VERSION 5.7 ;
BUSBITCHARS "[]" ;
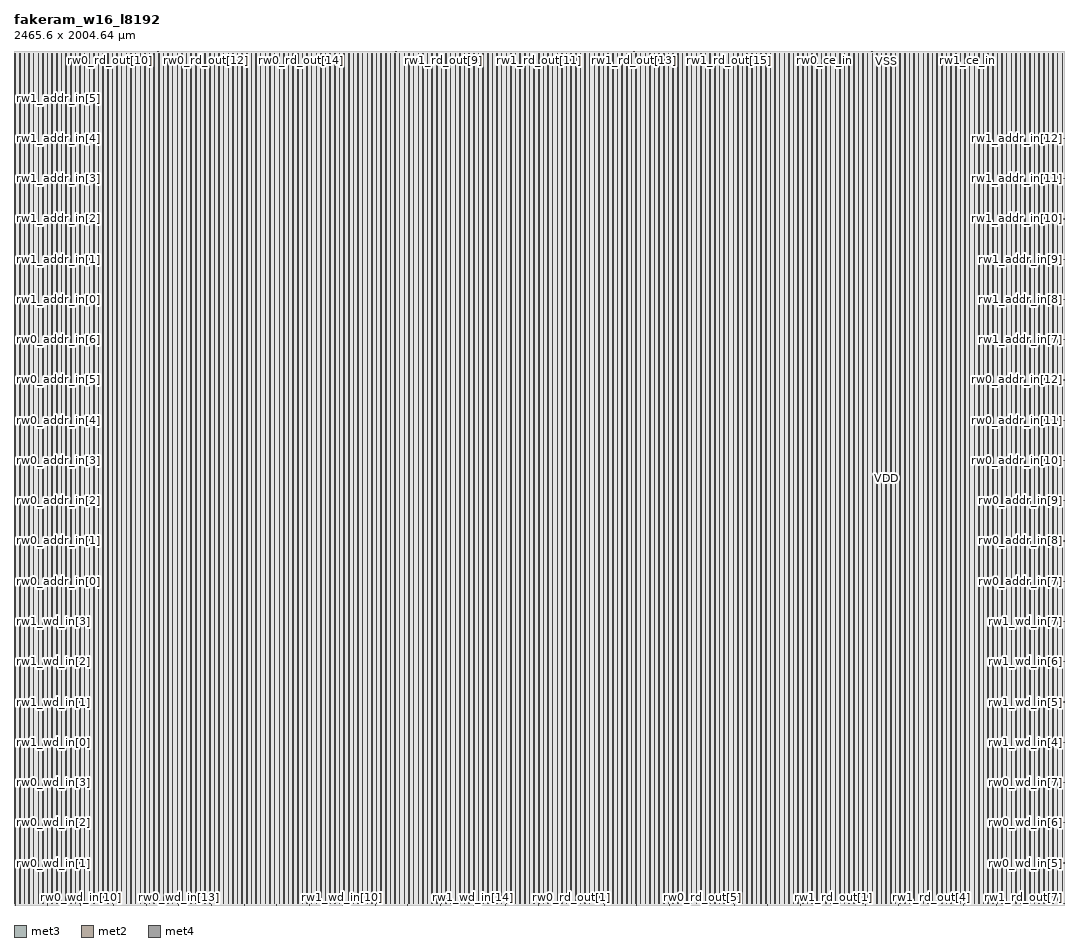
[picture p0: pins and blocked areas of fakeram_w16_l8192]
MACRO fakeram_w16_l8192
  FOREIGN fakeram_w16_l8192 0 0 ;
  SYMMETRY X Y R90 ;
  SIZE 2465.600 BY 2004.640 ;
  CLASS BLOCK ;
  PIN rw0_wd_in[0]
    DIRECTION INPUT ;
    USE SIGNAL ;
    SHAPE ABUTMENT ;
    PORT
      LAYER met3 ;
      RECT 0.000 3.930 0.900 4.230 ;
    END
  END rw0_wd_in[0]
  PIN rw0_wd_in[1]
    DIRECTION INPUT ;
    USE SIGNAL ;
    SHAPE ABUTMENT ;
    PORT
      LAYER met3 ;
      RECT 0.000 98.450 0.900 98.750 ;
    END
  END rw0_wd_in[1]
  PIN rw0_wd_in[2]
    DIRECTION INPUT ;
    USE SIGNAL ;
    SHAPE ABUTMENT ;
    PORT
      LAYER met3 ;
      RECT 0.000 192.970 0.900 193.270 ;
    END
  END rw0_wd_in[2]
  PIN rw0_wd_in[3]
    DIRECTION INPUT ;
    USE SIGNAL ;
    SHAPE ABUTMENT ;
    PORT
      LAYER met3 ;
      RECT 0.000 287.490 0.900 287.790 ;
    END
  END rw0_wd_in[3]
  PIN rw0_wd_in[4]
    DIRECTION INPUT ;
    USE SIGNAL ;
    SHAPE ABUTMENT ;
    PORT
      LAYER met3 ;
      RECT 2464.700 3.930 2465.600 4.230 ;
    END
  END rw0_wd_in[4]
  PIN rw0_wd_in[5]
    DIRECTION INPUT ;
    USE SIGNAL ;
    SHAPE ABUTMENT ;
    PORT
      LAYER met3 ;
      RECT 2464.700 98.450 2465.600 98.750 ;
    END
  END rw0_wd_in[5]
  PIN rw0_wd_in[6]
    DIRECTION INPUT ;
    USE SIGNAL ;
    SHAPE ABUTMENT ;
    PORT
      LAYER met3 ;
      RECT 2464.700 192.970 2465.600 193.270 ;
    END
  END rw0_wd_in[6]
  PIN rw0_wd_in[7]
    DIRECTION INPUT ;
    USE SIGNAL ;
    SHAPE ABUTMENT ;
    PORT
      LAYER met3 ;
      RECT 2464.700 287.490 2465.600 287.790 ;
    END
  END rw0_wd_in[7]
  PIN rw0_wd_in[8]
    DIRECTION INPUT ;
    USE SIGNAL ;
    SHAPE ABUTMENT ;
    PORT
      LAYER met2 ;
      RECT 2.690 0.000 2.830 0.420 ;
    END
  END rw0_wd_in[8]
  PIN rw0_wd_in[9]
    DIRECTION INPUT ;
    USE SIGNAL ;
    SHAPE ABUTMENT ;
    PORT
      LAYER met2 ;
      RECT 79.510 0.000 79.650 0.420 ;
    END
  END rw0_wd_in[9]
  PIN rw0_wd_in[10]
    DIRECTION INPUT ;
    USE SIGNAL ;
    SHAPE ABUTMENT ;
    PORT
      LAYER met2 ;
      RECT 156.330 0.000 156.470 0.420 ;
    END
  END rw0_wd_in[10]
  PIN rw0_wd_in[11]
    DIRECTION INPUT ;
    USE SIGNAL ;
    SHAPE ABUTMENT ;
    PORT
      LAYER met2 ;
      RECT 233.150 0.000 233.290 0.420 ;
    END
  END rw0_wd_in[11]
  PIN rw0_wd_in[12]
    DIRECTION INPUT ;
    USE SIGNAL ;
    SHAPE ABUTMENT ;
    PORT
      LAYER met2 ;
      RECT 309.970 0.000 310.110 0.420 ;
    END
  END rw0_wd_in[12]
  PIN rw0_wd_in[13]
    DIRECTION INPUT ;
    USE SIGNAL ;
    SHAPE ABUTMENT ;
    PORT
      LAYER met2 ;
      RECT 386.790 0.000 386.930 0.420 ;
    END
  END rw0_wd_in[13]
  PIN rw0_wd_in[14]
    DIRECTION INPUT ;
    USE SIGNAL ;
    SHAPE ABUTMENT ;
    PORT
      LAYER met2 ;
      RECT 463.610 0.000 463.750 0.420 ;
    END
  END rw0_wd_in[14]
  PIN rw0_wd_in[15]
    DIRECTION INPUT ;
    USE SIGNAL ;
    SHAPE ABUTMENT ;
    PORT
      LAYER met2 ;
      RECT 540.430 0.000 540.570 0.420 ;
    END
  END rw0_wd_in[15]
  PIN rw1_wd_in[0]
    DIRECTION INPUT ;
    USE SIGNAL ;
    SHAPE ABUTMENT ;
    PORT
      LAYER met3 ;
      RECT 0.000 382.010 0.900 382.310 ;
    END
  END rw1_wd_in[0]
  PIN rw1_wd_in[1]
    DIRECTION INPUT ;
    USE SIGNAL ;
    SHAPE ABUTMENT ;
    PORT
      LAYER met3 ;
      RECT 0.000 476.530 0.900 476.830 ;
    END
  END rw1_wd_in[1]
  PIN rw1_wd_in[2]
    DIRECTION INPUT ;
    USE SIGNAL ;
    SHAPE ABUTMENT ;
    PORT
      LAYER met3 ;
      RECT 0.000 571.050 0.900 571.350 ;
    END
  END rw1_wd_in[2]
  PIN rw1_wd_in[3]
    DIRECTION INPUT ;
    USE SIGNAL ;
    SHAPE ABUTMENT ;
    PORT
      LAYER met3 ;
      RECT 0.000 665.570 0.900 665.870 ;
    END
  END rw1_wd_in[3]
  PIN rw1_wd_in[4]
    DIRECTION INPUT ;
    USE SIGNAL ;
    SHAPE ABUTMENT ;
    PORT
      LAYER met3 ;
      RECT 2464.700 382.010 2465.600 382.310 ;
    END
  END rw1_wd_in[4]
  PIN rw1_wd_in[5]
    DIRECTION INPUT ;
    USE SIGNAL ;
    SHAPE ABUTMENT ;
    PORT
      LAYER met3 ;
      RECT 2464.700 476.530 2465.600 476.830 ;
    END
  END rw1_wd_in[5]
  PIN rw1_wd_in[6]
    DIRECTION INPUT ;
    USE SIGNAL ;
    SHAPE ABUTMENT ;
    PORT
      LAYER met3 ;
      RECT 2464.700 571.050 2465.600 571.350 ;
    END
  END rw1_wd_in[6]
  PIN rw1_wd_in[7]
    DIRECTION INPUT ;
    USE SIGNAL ;
    SHAPE ABUTMENT ;
    PORT
      LAYER met3 ;
      RECT 2464.700 665.570 2465.600 665.870 ;
    END
  END rw1_wd_in[7]
  PIN rw1_wd_in[8]
    DIRECTION INPUT ;
    USE SIGNAL ;
    SHAPE ABUTMENT ;
    PORT
      LAYER met2 ;
      RECT 617.250 0.000 617.390 0.420 ;
    END
  END rw1_wd_in[8]
  PIN rw1_wd_in[9]
    DIRECTION INPUT ;
    USE SIGNAL ;
    SHAPE ABUTMENT ;
    PORT
      LAYER met2 ;
      RECT 694.070 0.000 694.210 0.420 ;
    END
  END rw1_wd_in[9]
  PIN rw1_wd_in[10]
    DIRECTION INPUT ;
    USE SIGNAL ;
    SHAPE ABUTMENT ;
    PORT
      LAYER met2 ;
      RECT 770.890 0.000 771.030 0.420 ;
    END
  END rw1_wd_in[10]
  PIN rw1_wd_in[11]
    DIRECTION INPUT ;
    USE SIGNAL ;
    SHAPE ABUTMENT ;
    PORT
      LAYER met2 ;
      RECT 847.710 0.000 847.850 0.420 ;
    END
  END rw1_wd_in[11]
  PIN rw1_wd_in[12]
    DIRECTION INPUT ;
    USE SIGNAL ;
    SHAPE ABUTMENT ;
    PORT
      LAYER met2 ;
      RECT 924.530 0.000 924.670 0.420 ;
    END
  END rw1_wd_in[12]
  PIN rw1_wd_in[13]
    DIRECTION INPUT ;
    USE SIGNAL ;
    SHAPE ABUTMENT ;
    PORT
      LAYER met2 ;
      RECT 1001.350 0.000 1001.490 0.420 ;
    END
  END rw1_wd_in[13]
  PIN rw1_wd_in[14]
    DIRECTION INPUT ;
    USE SIGNAL ;
    SHAPE ABUTMENT ;
    PORT
      LAYER met2 ;
      RECT 1078.170 0.000 1078.310 0.420 ;
    END
  END rw1_wd_in[14]
  PIN rw1_wd_in[15]
    DIRECTION INPUT ;
    USE SIGNAL ;
    SHAPE ABUTMENT ;
    PORT
      LAYER met2 ;
      RECT 1154.990 0.000 1155.130 0.420 ;
    END
  END rw1_wd_in[15]
  PIN rw0_rd_out[0]
    DIRECTION OUTPUT ;
    USE SIGNAL ;
    SHAPE ABUTMENT ;
    PORT
      LAYER met2 ;
      RECT 1231.810 0.000 1231.950 0.420 ;
    END
  END rw0_rd_out[0]
  PIN rw0_rd_out[1]
    DIRECTION OUTPUT ;
    USE SIGNAL ;
    SHAPE ABUTMENT ;
    PORT
      LAYER met2 ;
      RECT 1308.630 0.000 1308.770 0.420 ;
    END
  END rw0_rd_out[1]
  PIN rw0_rd_out[2]
    DIRECTION OUTPUT ;
    USE SIGNAL ;
    SHAPE ABUTMENT ;
    PORT
      LAYER met2 ;
      RECT 1385.450 0.000 1385.590 0.420 ;
    END
  END rw0_rd_out[2]
  PIN rw0_rd_out[3]
    DIRECTION OUTPUT ;
    USE SIGNAL ;
    SHAPE ABUTMENT ;
    PORT
      LAYER met2 ;
      RECT 1462.270 0.000 1462.410 0.420 ;
    END
  END rw0_rd_out[3]
  PIN rw0_rd_out[4]
    DIRECTION OUTPUT ;
    USE SIGNAL ;
    SHAPE ABUTMENT ;
    PORT
      LAYER met2 ;
      RECT 1539.090 0.000 1539.230 0.420 ;
    END
  END rw0_rd_out[4]
  PIN rw0_rd_out[5]
    DIRECTION OUTPUT ;
    USE SIGNAL ;
    SHAPE ABUTMENT ;
    PORT
      LAYER met2 ;
      RECT 1615.910 0.000 1616.050 0.420 ;
    END
  END rw0_rd_out[5]
  PIN rw0_rd_out[6]
    DIRECTION OUTPUT ;
    USE SIGNAL ;
    SHAPE ABUTMENT ;
    PORT
      LAYER met2 ;
      RECT 1692.730 0.000 1692.870 0.420 ;
    END
  END rw0_rd_out[6]
  PIN rw0_rd_out[7]
    DIRECTION OUTPUT ;
    USE SIGNAL ;
    SHAPE ABUTMENT ;
    PORT
      LAYER met2 ;
      RECT 1769.550 0.000 1769.690 0.420 ;
    END
  END rw0_rd_out[7]
  PIN rw0_rd_out[8]
    DIRECTION OUTPUT ;
    USE SIGNAL ;
    SHAPE ABUTMENT ;
    PORT
      LAYER met2 ;
      RECT 2.690 2004.220 2.830 2004.640 ;
    END
  END rw0_rd_out[8]
  PIN rw0_rd_out[9]
    DIRECTION OUTPUT ;
    USE SIGNAL ;
    SHAPE ABUTMENT ;
    PORT
      LAYER met2 ;
      RECT 114.470 2004.220 114.610 2004.640 ;
    END
  END rw0_rd_out[9]
  PIN rw0_rd_out[10]
    DIRECTION OUTPUT ;
    USE SIGNAL ;
    SHAPE ABUTMENT ;
    PORT
      LAYER met2 ;
      RECT 226.250 2004.220 226.390 2004.640 ;
    END
  END rw0_rd_out[10]
  PIN rw0_rd_out[11]
    DIRECTION OUTPUT ;
    USE SIGNAL ;
    SHAPE ABUTMENT ;
    PORT
      LAYER met2 ;
      RECT 338.030 2004.220 338.170 2004.640 ;
    END
  END rw0_rd_out[11]
  PIN rw0_rd_out[12]
    DIRECTION OUTPUT ;
    USE SIGNAL ;
    SHAPE ABUTMENT ;
    PORT
      LAYER met2 ;
      RECT 449.810 2004.220 449.950 2004.640 ;
    END
  END rw0_rd_out[12]
  PIN rw0_rd_out[13]
    DIRECTION OUTPUT ;
    USE SIGNAL ;
    SHAPE ABUTMENT ;
    PORT
      LAYER met2 ;
      RECT 561.590 2004.220 561.730 2004.640 ;
    END
  END rw0_rd_out[13]
  PIN rw0_rd_out[14]
    DIRECTION OUTPUT ;
    USE SIGNAL ;
    SHAPE ABUTMENT ;
    PORT
      LAYER met2 ;
      RECT 673.370 2004.220 673.510 2004.640 ;
    END
  END rw0_rd_out[14]
  PIN rw0_rd_out[15]
    DIRECTION OUTPUT ;
    USE SIGNAL ;
    SHAPE ABUTMENT ;
    PORT
      LAYER met2 ;
      RECT 785.150 2004.220 785.290 2004.640 ;
    END
  END rw0_rd_out[15]
  PIN rw1_rd_out[0]
    DIRECTION OUTPUT ;
    USE SIGNAL ;
    SHAPE ABUTMENT ;
    PORT
      LAYER met2 ;
      RECT 1846.370 0.000 1846.510 0.420 ;
    END
  END rw1_rd_out[0]
  PIN rw1_rd_out[1]
    DIRECTION OUTPUT ;
    USE SIGNAL ;
    SHAPE ABUTMENT ;
    PORT
      LAYER met2 ;
      RECT 1923.190 0.000 1923.330 0.420 ;
    END
  END rw1_rd_out[1]
  PIN rw1_rd_out[2]
    DIRECTION OUTPUT ;
    USE SIGNAL ;
    SHAPE ABUTMENT ;
    PORT
      LAYER met2 ;
      RECT 2000.010 0.000 2000.150 0.420 ;
    END
  END rw1_rd_out[2]
  PIN rw1_rd_out[3]
    DIRECTION OUTPUT ;
    USE SIGNAL ;
    SHAPE ABUTMENT ;
    PORT
      LAYER met2 ;
      RECT 2076.830 0.000 2076.970 0.420 ;
    END
  END rw1_rd_out[3]
  PIN rw1_rd_out[4]
    DIRECTION OUTPUT ;
    USE SIGNAL ;
    SHAPE ABUTMENT ;
    PORT
      LAYER met2 ;
      RECT 2153.650 0.000 2153.790 0.420 ;
    END
  END rw1_rd_out[4]
  PIN rw1_rd_out[5]
    DIRECTION OUTPUT ;
    USE SIGNAL ;
    SHAPE ABUTMENT ;
    PORT
      LAYER met2 ;
      RECT 2230.470 0.000 2230.610 0.420 ;
    END
  END rw1_rd_out[5]
  PIN rw1_rd_out[6]
    DIRECTION OUTPUT ;
    USE SIGNAL ;
    SHAPE ABUTMENT ;
    PORT
      LAYER met2 ;
      RECT 2307.290 0.000 2307.430 0.420 ;
    END
  END rw1_rd_out[6]
  PIN rw1_rd_out[7]
    DIRECTION OUTPUT ;
    USE SIGNAL ;
    SHAPE ABUTMENT ;
    PORT
      LAYER met2 ;
      RECT 2384.110 0.000 2384.250 0.420 ;
    END
  END rw1_rd_out[7]
  PIN rw1_rd_out[8]
    DIRECTION OUTPUT ;
    USE SIGNAL ;
    SHAPE ABUTMENT ;
    PORT
      LAYER met2 ;
      RECT 896.930 2004.220 897.070 2004.640 ;
    END
  END rw1_rd_out[8]
  PIN rw1_rd_out[9]
    DIRECTION OUTPUT ;
    USE SIGNAL ;
    SHAPE ABUTMENT ;
    PORT
      LAYER met2 ;
      RECT 1008.710 2004.220 1008.850 2004.640 ;
    END
  END rw1_rd_out[9]
  PIN rw1_rd_out[10]
    DIRECTION OUTPUT ;
    USE SIGNAL ;
    SHAPE ABUTMENT ;
    PORT
      LAYER met2 ;
      RECT 1120.490 2004.220 1120.630 2004.640 ;
    END
  END rw1_rd_out[10]
  PIN rw1_rd_out[11]
    DIRECTION OUTPUT ;
    USE SIGNAL ;
    SHAPE ABUTMENT ;
    PORT
      LAYER met2 ;
      RECT 1232.270 2004.220 1232.410 2004.640 ;
    END
  END rw1_rd_out[11]
  PIN rw1_rd_out[12]
    DIRECTION OUTPUT ;
    USE SIGNAL ;
    SHAPE ABUTMENT ;
    PORT
      LAYER met2 ;
      RECT 1344.050 2004.220 1344.190 2004.640 ;
    END
  END rw1_rd_out[12]
  PIN rw1_rd_out[13]
    DIRECTION OUTPUT ;
    USE SIGNAL ;
    SHAPE ABUTMENT ;
    PORT
      LAYER met2 ;
      RECT 1455.830 2004.220 1455.970 2004.640 ;
    END
  END rw1_rd_out[13]
  PIN rw1_rd_out[14]
    DIRECTION OUTPUT ;
    USE SIGNAL ;
    SHAPE ABUTMENT ;
    PORT
      LAYER met2 ;
      RECT 1567.610 2004.220 1567.750 2004.640 ;
    END
  END rw1_rd_out[14]
  PIN rw1_rd_out[15]
    DIRECTION OUTPUT ;
    USE SIGNAL ;
    SHAPE ABUTMENT ;
    PORT
      LAYER met2 ;
      RECT 1679.390 2004.220 1679.530 2004.640 ;
    END
  END rw1_rd_out[15]
  PIN rw0_addr_in[0]
    DIRECTION INPUT ;
    USE SIGNAL ;
    SHAPE ABUTMENT ;
    PORT
      LAYER met3 ;
      RECT 0.000 760.090 0.900 760.390 ;
    END
  END rw0_addr_in[0]
  PIN rw0_addr_in[1]
    DIRECTION INPUT ;
    USE SIGNAL ;
    SHAPE ABUTMENT ;
    PORT
      LAYER met3 ;
      RECT 0.000 854.610 0.900 854.910 ;
    END
  END rw0_addr_in[1]
  PIN rw0_addr_in[2]
    DIRECTION INPUT ;
    USE SIGNAL ;
    SHAPE ABUTMENT ;
    PORT
      LAYER met3 ;
      RECT 0.000 949.130 0.900 949.430 ;
    END
  END rw0_addr_in[2]
  PIN rw0_addr_in[3]
    DIRECTION INPUT ;
    USE SIGNAL ;
    SHAPE ABUTMENT ;
    PORT
      LAYER met3 ;
      RECT 0.000 1043.650 0.900 1043.950 ;
    END
  END rw0_addr_in[3]
  PIN rw0_addr_in[4]
    DIRECTION INPUT ;
    USE SIGNAL ;
    SHAPE ABUTMENT ;
    PORT
      LAYER met3 ;
      RECT 0.000 1138.170 0.900 1138.470 ;
    END
  END rw0_addr_in[4]
  PIN rw0_addr_in[5]
    DIRECTION INPUT ;
    USE SIGNAL ;
    SHAPE ABUTMENT ;
    PORT
      LAYER met3 ;
      RECT 0.000 1232.690 0.900 1232.990 ;
    END
  END rw0_addr_in[5]
  PIN rw0_addr_in[6]
    DIRECTION INPUT ;
    USE SIGNAL ;
    SHAPE ABUTMENT ;
    PORT
      LAYER met3 ;
      RECT 0.000 1327.210 0.900 1327.510 ;
    END
  END rw0_addr_in[6]
  PIN rw0_addr_in[7]
    DIRECTION INPUT ;
    USE SIGNAL ;
    SHAPE ABUTMENT ;
    PORT
      LAYER met3 ;
      RECT 2464.700 760.090 2465.600 760.390 ;
    END
  END rw0_addr_in[7]
  PIN rw0_addr_in[8]
    DIRECTION INPUT ;
    USE SIGNAL ;
    SHAPE ABUTMENT ;
    PORT
      LAYER met3 ;
      RECT 2464.700 854.610 2465.600 854.910 ;
    END
  END rw0_addr_in[8]
  PIN rw0_addr_in[9]
    DIRECTION INPUT ;
    USE SIGNAL ;
    SHAPE ABUTMENT ;
    PORT
      LAYER met3 ;
      RECT 2464.700 949.130 2465.600 949.430 ;
    END
  END rw0_addr_in[9]
  PIN rw0_addr_in[10]
    DIRECTION INPUT ;
    USE SIGNAL ;
    SHAPE ABUTMENT ;
    PORT
      LAYER met3 ;
      RECT 2464.700 1043.650 2465.600 1043.950 ;
    END
  END rw0_addr_in[10]
  PIN rw0_addr_in[11]
    DIRECTION INPUT ;
    USE SIGNAL ;
    SHAPE ABUTMENT ;
    PORT
      LAYER met3 ;
      RECT 2464.700 1138.170 2465.600 1138.470 ;
    END
  END rw0_addr_in[11]
  PIN rw0_addr_in[12]
    DIRECTION INPUT ;
    USE SIGNAL ;
    SHAPE ABUTMENT ;
    PORT
      LAYER met3 ;
      RECT 2464.700 1232.690 2465.600 1232.990 ;
    END
  END rw0_addr_in[12]
  PIN rw1_addr_in[0]
    DIRECTION INPUT ;
    USE SIGNAL ;
    SHAPE ABUTMENT ;
    PORT
      LAYER met3 ;
      RECT 0.000 1421.730 0.900 1422.030 ;
    END
  END rw1_addr_in[0]
  PIN rw1_addr_in[1]
    DIRECTION INPUT ;
    USE SIGNAL ;
    SHAPE ABUTMENT ;
    PORT
      LAYER met3 ;
      RECT 0.000 1516.250 0.900 1516.550 ;
    END
  END rw1_addr_in[1]
  PIN rw1_addr_in[2]
    DIRECTION INPUT ;
    USE SIGNAL ;
    SHAPE ABUTMENT ;
    PORT
      LAYER met3 ;
      RECT 0.000 1610.770 0.900 1611.070 ;
    END
  END rw1_addr_in[2]
  PIN rw1_addr_in[3]
    DIRECTION INPUT ;
    USE SIGNAL ;
    SHAPE ABUTMENT ;
    PORT
      LAYER met3 ;
      RECT 0.000 1705.290 0.900 1705.590 ;
    END
  END rw1_addr_in[3]
  PIN rw1_addr_in[4]
    DIRECTION INPUT ;
    USE SIGNAL ;
    SHAPE ABUTMENT ;
    PORT
      LAYER met3 ;
      RECT 0.000 1799.810 0.900 1800.110 ;
    END
  END rw1_addr_in[4]
  PIN rw1_addr_in[5]
    DIRECTION INPUT ;
    USE SIGNAL ;
    SHAPE ABUTMENT ;
    PORT
      LAYER met3 ;
      RECT 0.000 1894.330 0.900 1894.630 ;
    END
  END rw1_addr_in[5]
  PIN rw1_addr_in[6]
    DIRECTION INPUT ;
    USE SIGNAL ;
    SHAPE ABUTMENT ;
    PORT
      LAYER met3 ;
      RECT 0.000 1988.850 0.900 1989.150 ;
    END
  END rw1_addr_in[6]
  PIN rw1_addr_in[7]
    DIRECTION INPUT ;
    USE SIGNAL ;
    SHAPE ABUTMENT ;
    PORT
      LAYER met3 ;
      RECT 2464.700 1327.210 2465.600 1327.510 ;
    END
  END rw1_addr_in[7]
  PIN rw1_addr_in[8]
    DIRECTION INPUT ;
    USE SIGNAL ;
    SHAPE ABUTMENT ;
    PORT
      LAYER met3 ;
      RECT 2464.700 1421.730 2465.600 1422.030 ;
    END
  END rw1_addr_in[8]
  PIN rw1_addr_in[9]
    DIRECTION INPUT ;
    USE SIGNAL ;
    SHAPE ABUTMENT ;
    PORT
      LAYER met3 ;
      RECT 2464.700 1516.250 2465.600 1516.550 ;
    END
  END rw1_addr_in[9]
  PIN rw1_addr_in[10]
    DIRECTION INPUT ;
    USE SIGNAL ;
    SHAPE ABUTMENT ;
    PORT
      LAYER met3 ;
      RECT 2464.700 1610.770 2465.600 1611.070 ;
    END
  END rw1_addr_in[10]
  PIN rw1_addr_in[11]
    DIRECTION INPUT ;
    USE SIGNAL ;
    SHAPE ABUTMENT ;
    PORT
      LAYER met3 ;
      RECT 2464.700 1705.290 2465.600 1705.590 ;
    END
  END rw1_addr_in[11]
  PIN rw1_addr_in[12]
    DIRECTION INPUT ;
    USE SIGNAL ;
    SHAPE ABUTMENT ;
    PORT
      LAYER met3 ;
      RECT 2464.700 1799.810 2465.600 1800.110 ;
    END
  END rw1_addr_in[12]
  PIN rw0_we_in
    DIRECTION INPUT ;
    USE SIGNAL ;
    SHAPE ABUTMENT ;
    PORT
      LAYER met2 ;
      RECT 1791.170 2004.220 1791.310 2004.640 ;
    END
  END rw0_we_in
  PIN rw0_ce_in
    DIRECTION INPUT ;
    USE SIGNAL ;
    SHAPE ABUTMENT ;
    PORT
      LAYER met2 ;
      RECT 1902.950 2004.220 1903.090 2004.640 ;
    END
  END rw0_ce_in
  PIN rw0_clk
    DIRECTION INPUT ;
    USE SIGNAL ;
    SHAPE ABUTMENT ;
    PORT
      LAYER met2 ;
      RECT 2014.730 2004.220 2014.870 2004.640 ;
    END
  END rw0_clk
  PIN rw1_we_in
    DIRECTION INPUT ;
    USE SIGNAL ;
    SHAPE ABUTMENT ;
    PORT
      LAYER met2 ;
      RECT 2126.510 2004.220 2126.650 2004.640 ;
    END
  END rw1_we_in
  PIN rw1_ce_in
    DIRECTION INPUT ;
    USE SIGNAL ;
    SHAPE ABUTMENT ;
    PORT
      LAYER met2 ;
      RECT 2238.290 2004.220 2238.430 2004.640 ;
    END
  END rw1_ce_in
  PIN rw1_clk
    DIRECTION INPUT ;
    USE SIGNAL ;
    SHAPE ABUTMENT ;
    PORT
      LAYER met2 ;
      RECT 2350.070 2004.220 2350.210 2004.640 ;
    END
  END rw1_clk
  PIN VSS
    DIRECTION INOUT ;
    USE GROUND ;
    PORT
      LAYER met4 ;
      RECT 2.160 4.080 3.360 2000.560 ;
      RECT 13.040 4.080 14.240 2000.560 ;
      RECT 23.920 4.080 25.120 2000.560 ;
      RECT 34.800 4.080 36.000 2000.560 ;
      RECT 45.680 4.080 46.880 2000.560 ;
      RECT 56.560 4.080 57.760 2000.560 ;
      RECT 67.440 4.080 68.640 2000.560 ;
      RECT 78.320 4.080 79.520 2000.560 ;
      RECT 89.200 4.080 90.400 2000.560 ;
      RECT 100.080 4.080 101.280 2000.560 ;
      RECT 110.960 4.080 112.160 2000.560 ;
      RECT 121.840 4.080 123.040 2000.560 ;
      RECT 132.720 4.080 133.920 2000.560 ;
      RECT 143.600 4.080 144.800 2000.560 ;
      RECT 154.480 4.080 155.680 2000.560 ;
      RECT 165.360 4.080 166.560 2000.560 ;
      RECT 176.240 4.080 177.440 2000.560 ;
      RECT 187.120 4.080 188.320 2000.560 ;
      RECT 198.000 4.080 199.200 2000.560 ;
      RECT 208.880 4.080 210.080 2000.560 ;
      RECT 219.760 4.080 220.960 2000.560 ;
      RECT 230.640 4.080 231.840 2000.560 ;
      RECT 241.520 4.080 242.720 2000.560 ;
      RECT 252.400 4.080 253.600 2000.560 ;
      RECT 263.280 4.080 264.480 2000.560 ;
      RECT 274.160 4.080 275.360 2000.560 ;
      RECT 285.040 4.080 286.240 2000.560 ;
      RECT 295.920 4.080 297.120 2000.560 ;
      RECT 306.800 4.080 308.000 2000.560 ;
      RECT 317.680 4.080 318.880 2000.560 ;
      RECT 328.560 4.080 329.760 2000.560 ;
      RECT 339.440 4.080 340.640 2000.560 ;
      RECT 350.320 4.080 351.520 2000.560 ;
      RECT 361.200 4.080 362.400 2000.560 ;
      RECT 372.080 4.080 373.280 2000.560 ;
      RECT 382.960 4.080 384.160 2000.560 ;
      RECT 393.840 4.080 395.040 2000.560 ;
      RECT 404.720 4.080 405.920 2000.560 ;
      RECT 415.600 4.080 416.800 2000.560 ;
      RECT 426.480 4.080 427.680 2000.560 ;
      RECT 437.360 4.080 438.560 2000.560 ;
      RECT 448.240 4.080 449.440 2000.560 ;
      RECT 459.120 4.080 460.320 2000.560 ;
      RECT 470.000 4.080 471.200 2000.560 ;
      RECT 480.880 4.080 482.080 2000.560 ;
      RECT 491.760 4.080 492.960 2000.560 ;
      RECT 502.640 4.080 503.840 2000.560 ;
      RECT 513.520 4.080 514.720 2000.560 ;
      RECT 524.400 4.080 525.600 2000.560 ;
      RECT 535.280 4.080 536.480 2000.560 ;
      RECT 546.160 4.080 547.360 2000.560 ;
      RECT 557.040 4.080 558.240 2000.560 ;
      RECT 567.920 4.080 569.120 2000.560 ;
      RECT 578.800 4.080 580.000 2000.560 ;
      RECT 589.680 4.080 590.880 2000.560 ;
      RECT 600.560 4.080 601.760 2000.560 ;
      RECT 611.440 4.080 612.640 2000.560 ;
      RECT 622.320 4.080 623.520 2000.560 ;
      RECT 633.200 4.080 634.400 2000.560 ;
      RECT 644.080 4.080 645.280 2000.560 ;
      RECT 654.960 4.080 656.160 2000.560 ;
      RECT 665.840 4.080 667.040 2000.560 ;
      RECT 676.720 4.080 677.920 2000.560 ;
      RECT 687.600 4.080 688.800 2000.560 ;
      RECT 698.480 4.080 699.680 2000.560 ;
      RECT 709.360 4.080 710.560 2000.560 ;
      RECT 720.240 4.080 721.440 2000.560 ;
      RECT 731.120 4.080 732.320 2000.560 ;
      RECT 742.000 4.080 743.200 2000.560 ;
      RECT 752.880 4.080 754.080 2000.560 ;
      RECT 763.760 4.080 764.960 2000.560 ;
      RECT 774.640 4.080 775.840 2000.560 ;
      RECT 785.520 4.080 786.720 2000.560 ;
      RECT 796.400 4.080 797.600 2000.560 ;
      RECT 807.280 4.080 808.480 2000.560 ;
      RECT 818.160 4.080 819.360 2000.560 ;
      RECT 829.040 4.080 830.240 2000.560 ;
      RECT 839.920 4.080 841.120 2000.560 ;
      RECT 850.800 4.080 852.000 2000.560 ;
      RECT 861.680 4.080 862.880 2000.560 ;
      RECT 872.560 4.080 873.760 2000.560 ;
      RECT 883.440 4.080 884.640 2000.560 ;
      RECT 894.320 4.080 895.520 2000.560 ;
      RECT 905.200 4.080 906.400 2000.560 ;
      RECT 916.080 4.080 917.280 2000.560 ;
      RECT 926.960 4.080 928.160 2000.560 ;
      RECT 937.840 4.080 939.040 2000.560 ;
      RECT 948.720 4.080 949.920 2000.560 ;
      RECT 959.600 4.080 960.800 2000.560 ;
      RECT 970.480 4.080 971.680 2000.560 ;
      RECT 981.360 4.080 982.560 2000.560 ;
      RECT 992.240 4.080 993.440 2000.560 ;
      RECT 1003.120 4.080 1004.320 2000.560 ;
      RECT 1014.000 4.080 1015.200 2000.560 ;
      RECT 1024.880 4.080 1026.080 2000.560 ;
      RECT 1035.760 4.080 1036.960 2000.560 ;
      RECT 1046.640 4.080 1047.840 2000.560 ;
      RECT 1057.520 4.080 1058.720 2000.560 ;
      RECT 1068.400 4.080 1069.600 2000.560 ;
      RECT 1079.280 4.080 1080.480 2000.560 ;
      RECT 1090.160 4.080 1091.360 2000.560 ;
      RECT 1101.040 4.080 1102.240 2000.560 ;
      RECT 1111.920 4.080 1113.120 2000.560 ;
      RECT 1122.800 4.080 1124.000 2000.560 ;
      RECT 1133.680 4.080 1134.880 2000.560 ;
      RECT 1144.560 4.080 1145.760 2000.560 ;
      RECT 1155.440 4.080 1156.640 2000.560 ;
      RECT 1166.320 4.080 1167.520 2000.560 ;
      RECT 1177.200 4.080 1178.400 2000.560 ;
      RECT 1188.080 4.080 1189.280 2000.560 ;
      RECT 1198.960 4.080 1200.160 2000.560 ;
      RECT 1209.840 4.080 1211.040 2000.560 ;
      RECT 1220.720 4.080 1221.920 2000.560 ;
      RECT 1231.600 4.080 1232.800 2000.560 ;
      RECT 1242.480 4.080 1243.680 2000.560 ;
      RECT 1253.360 4.080 1254.560 2000.560 ;
      RECT 1264.240 4.080 1265.440 2000.560 ;
      RECT 1275.120 4.080 1276.320 2000.560 ;
      RECT 1286.000 4.080 1287.200 2000.560 ;
      RECT 1296.880 4.080 1298.080 2000.560 ;
      RECT 1307.760 4.080 1308.960 2000.560 ;
      RECT 1318.640 4.080 1319.840 2000.560 ;
      RECT 1329.520 4.080 1330.720 2000.560 ;
      RECT 1340.400 4.080 1341.600 2000.560 ;
      RECT 1351.280 4.080 1352.480 2000.560 ;
      RECT 1362.160 4.080 1363.360 2000.560 ;
      RECT 1373.040 4.080 1374.240 2000.560 ;
      RECT 1383.920 4.080 1385.120 2000.560 ;
      RECT 1394.800 4.080 1396.000 2000.560 ;
      RECT 1405.680 4.080 1406.880 2000.560 ;
      RECT 1416.560 4.080 1417.760 2000.560 ;
      RECT 1427.440 4.080 1428.640 2000.560 ;
      RECT 1438.320 4.080 1439.520 2000.560 ;
      RECT 1449.200 4.080 1450.400 2000.560 ;
      RECT 1460.080 4.080 1461.280 2000.560 ;
      RECT 1470.960 4.080 1472.160 2000.560 ;
      RECT 1481.840 4.080 1483.040 2000.560 ;
      RECT 1492.720 4.080 1493.920 2000.560 ;
      RECT 1503.600 4.080 1504.800 2000.560 ;
      RECT 1514.480 4.080 1515.680 2000.560 ;
      RECT 1525.360 4.080 1526.560 2000.560 ;
      RECT 1536.240 4.080 1537.440 2000.560 ;
      RECT 1547.120 4.080 1548.320 2000.560 ;
      RECT 1558.000 4.080 1559.200 2000.560 ;
      RECT 1568.880 4.080 1570.080 2000.560 ;
      RECT 1579.760 4.080 1580.960 2000.560 ;
      RECT 1590.640 4.080 1591.840 2000.560 ;
      RECT 1601.520 4.080 1602.720 2000.560 ;
      RECT 1612.400 4.080 1613.600 2000.560 ;
      RECT 1623.280 4.080 1624.480 2000.560 ;
      RECT 1634.160 4.080 1635.360 2000.560 ;
      RECT 1645.040 4.080 1646.240 2000.560 ;
      RECT 1655.920 4.080 1657.120 2000.560 ;
      RECT 1666.800 4.080 1668.000 2000.560 ;
      RECT 1677.680 4.080 1678.880 2000.560 ;
      RECT 1688.560 4.080 1689.760 2000.560 ;
      RECT 1699.440 4.080 1700.640 2000.560 ;
      RECT 1710.320 4.080 1711.520 2000.560 ;
      RECT 1721.200 4.080 1722.400 2000.560 ;
      RECT 1732.080 4.080 1733.280 2000.560 ;
      RECT 1742.960 4.080 1744.160 2000.560 ;
      RECT 1753.840 4.080 1755.040 2000.560 ;
      RECT 1764.720 4.080 1765.920 2000.560 ;
      RECT 1775.600 4.080 1776.800 2000.560 ;
      RECT 1786.480 4.080 1787.680 2000.560 ;
      RECT 1797.360 4.080 1798.560 2000.560 ;
      RECT 1808.240 4.080 1809.440 2000.560 ;
      RECT 1819.120 4.080 1820.320 2000.560 ;
      RECT 1830.000 4.080 1831.200 2000.560 ;
      RECT 1840.880 4.080 1842.080 2000.560 ;
      RECT 1851.760 4.080 1852.960 2000.560 ;
      RECT 1862.640 4.080 1863.840 2000.560 ;
      RECT 1873.520 4.080 1874.720 2000.560 ;
      RECT 1884.400 4.080 1885.600 2000.560 ;
      RECT 1895.280 4.080 1896.480 2000.560 ;
      RECT 1906.160 4.080 1907.360 2000.560 ;
      RECT 1917.040 4.080 1918.240 2000.560 ;
      RECT 1927.920 4.080 1929.120 2000.560 ;
      RECT 1938.800 4.080 1940.000 2000.560 ;
      RECT 1949.680 4.080 1950.880 2000.560 ;
      RECT 1960.560 4.080 1961.760 2000.560 ;
      RECT 1971.440 4.080 1972.640 2000.560 ;
      RECT 1982.320 4.080 1983.520 2000.560 ;
      RECT 1993.200 4.080 1994.400 2000.560 ;
      RECT 2004.080 4.080 2005.280 2000.560 ;
      RECT 2014.960 4.080 2016.160 2000.560 ;
      RECT 2025.840 4.080 2027.040 2000.560 ;
      RECT 2036.720 4.080 2037.920 2000.560 ;
      RECT 2047.600 4.080 2048.800 2000.560 ;
      RECT 2058.480 4.080 2059.680 2000.560 ;
      RECT 2069.360 4.080 2070.560 2000.560 ;
      RECT 2080.240 4.080 2081.440 2000.560 ;
      RECT 2091.120 4.080 2092.320 2000.560 ;
      RECT 2102.000 4.080 2103.200 2000.560 ;
      RECT 2112.880 4.080 2114.080 2000.560 ;
      RECT 2123.760 4.080 2124.960 2000.560 ;
      RECT 2134.640 4.080 2135.840 2000.560 ;
      RECT 2145.520 4.080 2146.720 2000.560 ;
      RECT 2156.400 4.080 2157.600 2000.560 ;
      RECT 2167.280 4.080 2168.480 2000.560 ;
      RECT 2178.160 4.080 2179.360 2000.560 ;
      RECT 2189.040 4.080 2190.240 2000.560 ;
      RECT 2199.920 4.080 2201.120 2000.560 ;
      RECT 2210.800 4.080 2212.000 2000.560 ;
      RECT 2221.680 4.080 2222.880 2000.560 ;
      RECT 2232.560 4.080 2233.760 2000.560 ;
      RECT 2243.440 4.080 2244.640 2000.560 ;
      RECT 2254.320 4.080 2255.520 2000.560 ;
      RECT 2265.200 4.080 2266.400 2000.560 ;
      RECT 2276.080 4.080 2277.280 2000.560 ;
      RECT 2286.960 4.080 2288.160 2000.560 ;
      RECT 2297.840 4.080 2299.040 2000.560 ;
      RECT 2308.720 4.080 2309.920 2000.560 ;
      RECT 2319.600 4.080 2320.800 2000.560 ;
      RECT 2330.480 4.080 2331.680 2000.560 ;
      RECT 2341.360 4.080 2342.560 2000.560 ;
      RECT 2352.240 4.080 2353.440 2000.560 ;
      RECT 2363.120 4.080 2364.320 2000.560 ;
      RECT 2374.000 4.080 2375.200 2000.560 ;
      RECT 2384.880 4.080 2386.080 2000.560 ;
      RECT 2395.760 4.080 2396.960 2000.560 ;
      RECT 2406.640 4.080 2407.840 2000.560 ;
      RECT 2417.520 4.080 2418.720 2000.560 ;
      RECT 2428.400 4.080 2429.600 2000.560 ;
      RECT 2439.280 4.080 2440.480 2000.560 ;
      RECT 2450.160 4.080 2451.360 2000.560 ;
      RECT 2461.040 4.080 2462.240 2000.560 ;
    END
  END VSS
  PIN VDD
    DIRECTION INOUT ;
    USE POWER ;
    PORT
      LAYER met4 ;
      RECT 2.160 4.080 3.360 2000.560 ;
      RECT 13.040 4.080 14.240 2000.560 ;
      RECT 23.920 4.080 25.120 2000.560 ;
      RECT 34.800 4.080 36.000 2000.560 ;
      RECT 45.680 4.080 46.880 2000.560 ;
      RECT 56.560 4.080 57.760 2000.560 ;
      RECT 67.440 4.080 68.640 2000.560 ;
      RECT 78.320 4.080 79.520 2000.560 ;
      RECT 89.200 4.080 90.400 2000.560 ;
      RECT 100.080 4.080 101.280 2000.560 ;
      RECT 110.960 4.080 112.160 2000.560 ;
      RECT 121.840 4.080 123.040 2000.560 ;
      RECT 132.720 4.080 133.920 2000.560 ;
      RECT 143.600 4.080 144.800 2000.560 ;
      RECT 154.480 4.080 155.680 2000.560 ;
      RECT 165.360 4.080 166.560 2000.560 ;
      RECT 176.240 4.080 177.440 2000.560 ;
      RECT 187.120 4.080 188.320 2000.560 ;
      RECT 198.000 4.080 199.200 2000.560 ;
      RECT 208.880 4.080 210.080 2000.560 ;
      RECT 219.760 4.080 220.960 2000.560 ;
      RECT 230.640 4.080 231.840 2000.560 ;
      RECT 241.520 4.080 242.720 2000.560 ;
      RECT 252.400 4.080 253.600 2000.560 ;
      RECT 263.280 4.080 264.480 2000.560 ;
      RECT 274.160 4.080 275.360 2000.560 ;
      RECT 285.040 4.080 286.240 2000.560 ;
      RECT 295.920 4.080 297.120 2000.560 ;
      RECT 306.800 4.080 308.000 2000.560 ;
      RECT 317.680 4.080 318.880 2000.560 ;
      RECT 328.560 4.080 329.760 2000.560 ;
      RECT 339.440 4.080 340.640 2000.560 ;
      RECT 350.320 4.080 351.520 2000.560 ;
      RECT 361.200 4.080 362.400 2000.560 ;
      RECT 372.080 4.080 373.280 2000.560 ;
      RECT 382.960 4.080 384.160 2000.560 ;
      RECT 393.840 4.080 395.040 2000.560 ;
      RECT 404.720 4.080 405.920 2000.560 ;
      RECT 415.600 4.080 416.800 2000.560 ;
      RECT 426.480 4.080 427.680 2000.560 ;
      RECT 437.360 4.080 438.560 2000.560 ;
      RECT 448.240 4.080 449.440 2000.560 ;
      RECT 459.120 4.080 460.320 2000.560 ;
      RECT 470.000 4.080 471.200 2000.560 ;
      RECT 480.880 4.080 482.080 2000.560 ;
      RECT 491.760 4.080 492.960 2000.560 ;
      RECT 502.640 4.080 503.840 2000.560 ;
      RECT 513.520 4.080 514.720 2000.560 ;
      RECT 524.400 4.080 525.600 2000.560 ;
      RECT 535.280 4.080 536.480 2000.560 ;
      RECT 546.160 4.080 547.360 2000.560 ;
      RECT 557.040 4.080 558.240 2000.560 ;
      RECT 567.920 4.080 569.120 2000.560 ;
      RECT 578.800 4.080 580.000 2000.560 ;
      RECT 589.680 4.080 590.880 2000.560 ;
      RECT 600.560 4.080 601.760 2000.560 ;
      RECT 611.440 4.080 612.640 2000.560 ;
      RECT 622.320 4.080 623.520 2000.560 ;
      RECT 633.200 4.080 634.400 2000.560 ;
      RECT 644.080 4.080 645.280 2000.560 ;
      RECT 654.960 4.080 656.160 2000.560 ;
      RECT 665.840 4.080 667.040 2000.560 ;
      RECT 676.720 4.080 677.920 2000.560 ;
      RECT 687.600 4.080 688.800 2000.560 ;
      RECT 698.480 4.080 699.680 2000.560 ;
      RECT 709.360 4.080 710.560 2000.560 ;
      RECT 720.240 4.080 721.440 2000.560 ;
      RECT 731.120 4.080 732.320 2000.560 ;
      RECT 742.000 4.080 743.200 2000.560 ;
      RECT 752.880 4.080 754.080 2000.560 ;
      RECT 763.760 4.080 764.960 2000.560 ;
      RECT 774.640 4.080 775.840 2000.560 ;
      RECT 785.520 4.080 786.720 2000.560 ;
      RECT 796.400 4.080 797.600 2000.560 ;
      RECT 807.280 4.080 808.480 2000.560 ;
      RECT 818.160 4.080 819.360 2000.560 ;
      RECT 829.040 4.080 830.240 2000.560 ;
      RECT 839.920 4.080 841.120 2000.560 ;
      RECT 850.800 4.080 852.000 2000.560 ;
      RECT 861.680 4.080 862.880 2000.560 ;
      RECT 872.560 4.080 873.760 2000.560 ;
      RECT 883.440 4.080 884.640 2000.560 ;
      RECT 894.320 4.080 895.520 2000.560 ;
      RECT 905.200 4.080 906.400 2000.560 ;
      RECT 916.080 4.080 917.280 2000.560 ;
      RECT 926.960 4.080 928.160 2000.560 ;
      RECT 937.840 4.080 939.040 2000.560 ;
      RECT 948.720 4.080 949.920 2000.560 ;
      RECT 959.600 4.080 960.800 2000.560 ;
      RECT 970.480 4.080 971.680 2000.560 ;
      RECT 981.360 4.080 982.560 2000.560 ;
      RECT 992.240 4.080 993.440 2000.560 ;
      RECT 1003.120 4.080 1004.320 2000.560 ;
      RECT 1014.000 4.080 1015.200 2000.560 ;
      RECT 1024.880 4.080 1026.080 2000.560 ;
      RECT 1035.760 4.080 1036.960 2000.560 ;
      RECT 1046.640 4.080 1047.840 2000.560 ;
      RECT 1057.520 4.080 1058.720 2000.560 ;
      RECT 1068.400 4.080 1069.600 2000.560 ;
      RECT 1079.280 4.080 1080.480 2000.560 ;
      RECT 1090.160 4.080 1091.360 2000.560 ;
      RECT 1101.040 4.080 1102.240 2000.560 ;
      RECT 1111.920 4.080 1113.120 2000.560 ;
      RECT 1122.800 4.080 1124.000 2000.560 ;
      RECT 1133.680 4.080 1134.880 2000.560 ;
      RECT 1144.560 4.080 1145.760 2000.560 ;
      RECT 1155.440 4.080 1156.640 2000.560 ;
      RECT 1166.320 4.080 1167.520 2000.560 ;
      RECT 1177.200 4.080 1178.400 2000.560 ;
      RECT 1188.080 4.080 1189.280 2000.560 ;
      RECT 1198.960 4.080 1200.160 2000.560 ;
      RECT 1209.840 4.080 1211.040 2000.560 ;
      RECT 1220.720 4.080 1221.920 2000.560 ;
      RECT 1231.600 4.080 1232.800 2000.560 ;
      RECT 1242.480 4.080 1243.680 2000.560 ;
      RECT 1253.360 4.080 1254.560 2000.560 ;
      RECT 1264.240 4.080 1265.440 2000.560 ;
      RECT 1275.120 4.080 1276.320 2000.560 ;
      RECT 1286.000 4.080 1287.200 2000.560 ;
      RECT 1296.880 4.080 1298.080 2000.560 ;
      RECT 1307.760 4.080 1308.960 2000.560 ;
      RECT 1318.640 4.080 1319.840 2000.560 ;
      RECT 1329.520 4.080 1330.720 2000.560 ;
      RECT 1340.400 4.080 1341.600 2000.560 ;
      RECT 1351.280 4.080 1352.480 2000.560 ;
      RECT 1362.160 4.080 1363.360 2000.560 ;
      RECT 1373.040 4.080 1374.240 2000.560 ;
      RECT 1383.920 4.080 1385.120 2000.560 ;
      RECT 1394.800 4.080 1396.000 2000.560 ;
      RECT 1405.680 4.080 1406.880 2000.560 ;
      RECT 1416.560 4.080 1417.760 2000.560 ;
      RECT 1427.440 4.080 1428.640 2000.560 ;
      RECT 1438.320 4.080 1439.520 2000.560 ;
      RECT 1449.200 4.080 1450.400 2000.560 ;
      RECT 1460.080 4.080 1461.280 2000.560 ;
      RECT 1470.960 4.080 1472.160 2000.560 ;
      RECT 1481.840 4.080 1483.040 2000.560 ;
      RECT 1492.720 4.080 1493.920 2000.560 ;
      RECT 1503.600 4.080 1504.800 2000.560 ;
      RECT 1514.480 4.080 1515.680 2000.560 ;
      RECT 1525.360 4.080 1526.560 2000.560 ;
      RECT 1536.240 4.080 1537.440 2000.560 ;
      RECT 1547.120 4.080 1548.320 2000.560 ;
      RECT 1558.000 4.080 1559.200 2000.560 ;
      RECT 1568.880 4.080 1570.080 2000.560 ;
      RECT 1579.760 4.080 1580.960 2000.560 ;
      RECT 1590.640 4.080 1591.840 2000.560 ;
      RECT 1601.520 4.080 1602.720 2000.560 ;
      RECT 1612.400 4.080 1613.600 2000.560 ;
      RECT 1623.280 4.080 1624.480 2000.560 ;
      RECT 1634.160 4.080 1635.360 2000.560 ;
      RECT 1645.040 4.080 1646.240 2000.560 ;
      RECT 1655.920 4.080 1657.120 2000.560 ;
      RECT 1666.800 4.080 1668.000 2000.560 ;
      RECT 1677.680 4.080 1678.880 2000.560 ;
      RECT 1688.560 4.080 1689.760 2000.560 ;
      RECT 1699.440 4.080 1700.640 2000.560 ;
      RECT 1710.320 4.080 1711.520 2000.560 ;
      RECT 1721.200 4.080 1722.400 2000.560 ;
      RECT 1732.080 4.080 1733.280 2000.560 ;
      RECT 1742.960 4.080 1744.160 2000.560 ;
      RECT 1753.840 4.080 1755.040 2000.560 ;
      RECT 1764.720 4.080 1765.920 2000.560 ;
      RECT 1775.600 4.080 1776.800 2000.560 ;
      RECT 1786.480 4.080 1787.680 2000.560 ;
      RECT 1797.360 4.080 1798.560 2000.560 ;
      RECT 1808.240 4.080 1809.440 2000.560 ;
      RECT 1819.120 4.080 1820.320 2000.560 ;
      RECT 1830.000 4.080 1831.200 2000.560 ;
      RECT 1840.880 4.080 1842.080 2000.560 ;
      RECT 1851.760 4.080 1852.960 2000.560 ;
      RECT 1862.640 4.080 1863.840 2000.560 ;
      RECT 1873.520 4.080 1874.720 2000.560 ;
      RECT 1884.400 4.080 1885.600 2000.560 ;
      RECT 1895.280 4.080 1896.480 2000.560 ;
      RECT 1906.160 4.080 1907.360 2000.560 ;
      RECT 1917.040 4.080 1918.240 2000.560 ;
      RECT 1927.920 4.080 1929.120 2000.560 ;
      RECT 1938.800 4.080 1940.000 2000.560 ;
      RECT 1949.680 4.080 1950.880 2000.560 ;
      RECT 1960.560 4.080 1961.760 2000.560 ;
      RECT 1971.440 4.080 1972.640 2000.560 ;
      RECT 1982.320 4.080 1983.520 2000.560 ;
      RECT 1993.200 4.080 1994.400 2000.560 ;
      RECT 2004.080 4.080 2005.280 2000.560 ;
      RECT 2014.960 4.080 2016.160 2000.560 ;
      RECT 2025.840 4.080 2027.040 2000.560 ;
      RECT 2036.720 4.080 2037.920 2000.560 ;
      RECT 2047.600 4.080 2048.800 2000.560 ;
      RECT 2058.480 4.080 2059.680 2000.560 ;
      RECT 2069.360 4.080 2070.560 2000.560 ;
      RECT 2080.240 4.080 2081.440 2000.560 ;
      RECT 2091.120 4.080 2092.320 2000.560 ;
      RECT 2102.000 4.080 2103.200 2000.560 ;
      RECT 2112.880 4.080 2114.080 2000.560 ;
      RECT 2123.760 4.080 2124.960 2000.560 ;
      RECT 2134.640 4.080 2135.840 2000.560 ;
      RECT 2145.520 4.080 2146.720 2000.560 ;
      RECT 2156.400 4.080 2157.600 2000.560 ;
      RECT 2167.280 4.080 2168.480 2000.560 ;
      RECT 2178.160 4.080 2179.360 2000.560 ;
      RECT 2189.040 4.080 2190.240 2000.560 ;
      RECT 2199.920 4.080 2201.120 2000.560 ;
      RECT 2210.800 4.080 2212.000 2000.560 ;
      RECT 2221.680 4.080 2222.880 2000.560 ;
      RECT 2232.560 4.080 2233.760 2000.560 ;
      RECT 2243.440 4.080 2244.640 2000.560 ;
      RECT 2254.320 4.080 2255.520 2000.560 ;
      RECT 2265.200 4.080 2266.400 2000.560 ;
      RECT 2276.080 4.080 2277.280 2000.560 ;
      RECT 2286.960 4.080 2288.160 2000.560 ;
      RECT 2297.840 4.080 2299.040 2000.560 ;
      RECT 2308.720 4.080 2309.920 2000.560 ;
      RECT 2319.600 4.080 2320.800 2000.560 ;
      RECT 2330.480 4.080 2331.680 2000.560 ;
      RECT 2341.360 4.080 2342.560 2000.560 ;
      RECT 2352.240 4.080 2353.440 2000.560 ;
      RECT 2363.120 4.080 2364.320 2000.560 ;
      RECT 2374.000 4.080 2375.200 2000.560 ;
      RECT 2384.880 4.080 2386.080 2000.560 ;
      RECT 2395.760 4.080 2396.960 2000.560 ;
      RECT 2406.640 4.080 2407.840 2000.560 ;
      RECT 2417.520 4.080 2418.720 2000.560 ;
      RECT 2428.400 4.080 2429.600 2000.560 ;
      RECT 2439.280 4.080 2440.480 2000.560 ;
      RECT 2450.160 4.080 2451.360 2000.560 ;
      RECT 2461.040 4.080 2462.240 2000.560 ;
    END
  END VDD
  OBS
    LAYER met1 ;
    RECT 0 0 2465.600 2004.640 ;
    LAYER met2 ;
    RECT 0 0 2465.600 2004.640 ;
    LAYER met3 ;
    RECT 0 0 2465.600 2004.640 ;
    LAYER met4 ;
    RECT 0 0 2465.600 2004.640 ;
  END
END fakeram_w16_l8192

END LIBRARY
